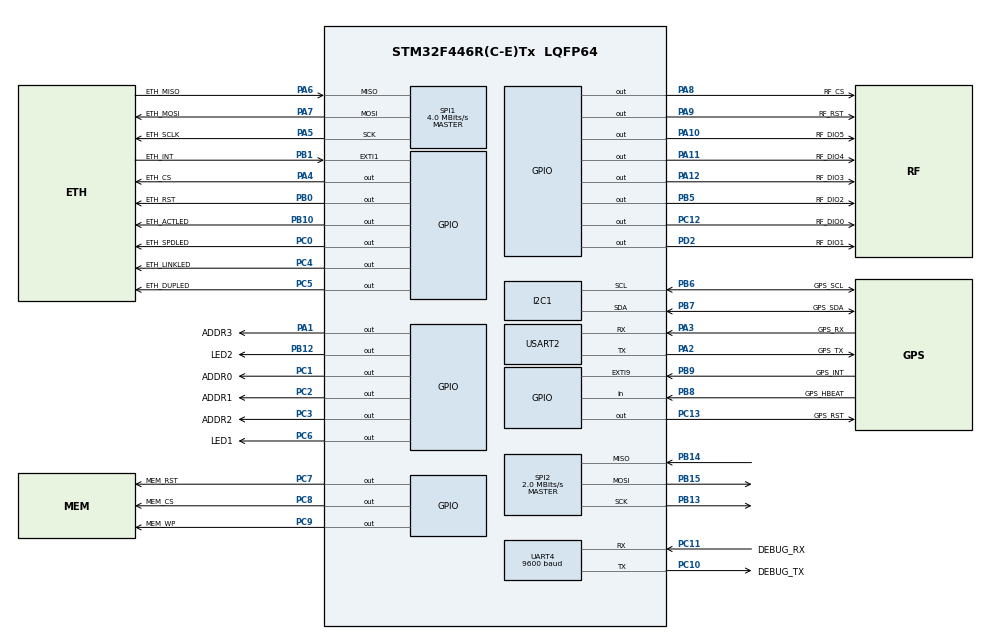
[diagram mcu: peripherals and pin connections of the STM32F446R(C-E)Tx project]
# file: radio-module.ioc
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Mcu.Family=STM32F4
Mcu.Name=STM32F446R(C-E)Tx
Mcu.Package=LQFP64
NVIC.EXTI1_IRQn=true\:0\:0\:false\:false\:true\:true\:true\:true
NVIC.EXTI9_5_IRQn=true\:0\:0\:false\:false\:true\:true\:true\:true
NVIC.I2C1_ER_IRQn=true\:0\:0\:false\:false\:true\:true\:true\:true
NVIC.I2C1_EV_IRQn=true\:0\:0\:false\:false\:true\:true\:true\:true
NVIC.PriorityGroup=NVIC_PRIORITYGROUP_4
NVIC.SPI1_IRQn=true\:0\:0\:false\:false\:true\:true\:true\:true
NVIC.SPI2_IRQn=true\:0\:0\:false\:false\:true\:true\:true\:true
NVIC.UART4_IRQn=true\:0\:0\:false\:false\:true\:true\:true\:true
NVIC.USART2_IRQn=true\:0\:0\:false\:false\:true\:true\:true\:true
PA1.GPIO_Label=ADDR3
PA1.Signal=GPIO_Output
PA10.GPIO_Label=RF_DIO5
PA10.Signal=GPIO_Output
PA11.GPIO_Label=RF_DIO4
PA11.Signal=GPIO_Output
PA12.GPIO_Label=RF_DIO3
PA12.Signal=GPIO_Output
PA2.GPIO_Label=GPS_TX
PA2.Mode=Asynchronous
PA2.Signal=USART2_TX
PA3.GPIO_Label=GPS_RX
PA3.Mode=Asynchronous
PA3.Signal=USART2_RX
PA4.GPIO_Label=ETH_CS
PA4.Signal=GPIO_Output
PA5.GPIO_Label=ETH_SCLK
PA5.Mode=Full_Duplex_Master
PA5.Signal=SPI1_SCK
PA6.GPIO_Label=ETH_MISO
PA6.Mode=Full_Duplex_Master
PA6.Signal=SPI1_MISO
PA7.GPIO_Label=ETH_MOSI
PA7.Mode=Full_Duplex_Master
PA7.Signal=SPI1_MOSI
PA8.GPIO_Label=RF_CS
PA8.Signal=GPIO_Output
PA9.GPIO_Label=RF_RST
PA9.PinState=GPIO_PIN_SET
PA9.Signal=GPIO_Output
PB0.GPIO_Label=ETH_RST
PB0.PinState=GPIO_PIN_SET
PB0.Signal=GPIO_Output
PB1.GPIO_Label=ETH_INT
PB1.Signal=GPXTI1
PB10.GPIO_Label=ETH_ACTLED
PB10.Signal=GPIO_Output
PB12.GPIO_Label=LED2
PB12.Signal=GPIO_Output
PB13.Mode=Full_Duplex_Master
PB13.Signal=SPI2_SCK
PB14.Mode=Full_Duplex_Master
PB14.Signal=SPI2_MISO
PB15.Mode=Full_Duplex_Master
PB15.Signal=SPI2_MOSI
PB5.GPIO_Label=RF_DIO2
PB5.Signal=GPIO_Output
PB6.GPIO_Label=GPS_SCL
PB6.Mode=I2C
PB6.Signal=I2C1_SCL
PB7.GPIO_Label=GPS_SDA
PB7.Mode=I2C
PB7.Signal=I2C1_SDA
PB8.GPIO_Label=GPS_HBEAT
PB8.Signal=GPIO_Input
PB9.GPIO_Label=GPS_INT
PB9.Signal=GPXTI9
PC0.GPIO_Label=ETH_SPDLED
PC0.Signal=GPIO_Output
PC1.GPIO_Label=ADDR0
PC1.Signal=GPIO_Output
PC10.GPIO_Label=DEBUG_TX
PC10.Mode=Asynchronous
PC10.Signal=UART4_TX
PC11.GPIO_Label=DEBUG_RX
PC11.Mode=Asynchronous
PC11.Signal=UART4_RX
PC12.GPIO_Label=RF_DIO0
PC12.Signal=GPIO_Output
PC13.GPIO_Label=GPS_RST
PC13.PinState=GPIO_PIN_SET
PC13.Signal=GPIO_Output
PC2.GPIO_Label=ADDR1
PC2.Signal=GPIO_Output
PC3.GPIO_Label=ADDR2
PC3.Signal=GPIO_Output
PC4.GPIO_Label=ETH_LINKLED
PC4.Signal=GPIO_Output
PC5.GPIO_Label=ETH_DUPLED
PC5.Signal=GPIO_Output
PC6.GPIO_Label=LED1
PC6.Signal=GPIO_Output
PC7.GPIO_Label=MEM_RST
PC7.PinState=GPIO_PIN_SET
PC7.Signal=GPIO_Output
PC8.GPIO_Label=MEM_CS
PC8.Signal=GPIO_Output
PC9.GPIO_Label=MEM_WP
PC9.Signal=GPIO_Output
PD2.GPIO_Label=RF_DIO1
PD2.Signal=GPIO_Output
ProjectManager.HeapSize=0x200
ProjectManager.StackSize=0x400
ProjectManager.TargetToolchain=Makefile
RCC.AHBFreq_Value=16000000
RCC.APB1CLKDivider=RCC_HCLK_DIV4
RCC.APB1Freq_Value=4000000
RCC.APB1TimFreq_Value=8000000
RCC.APB2CLKDivider=RCC_HCLK_DIV2
RCC.APB2Freq_Value=8000000
RCC.APB2TimFreq_Value=16000000
RCC.CortexFreq_Value=16000000
RCC.HCLKFreq_Value=16000000
RCC.PLLM=8
RCC.PLLN=180
RCC.SYSCLKFreq_VALUE=16000000
RCC.USBFreq_Value=180000000
RCC.VCOOutputFreq_Value=360000000
SPI1.CalculateBaudRate=4.0 MBits/s
SPI1.Direction=SPI_DIRECTION_2LINES
SPI1.Mode=SPI_MODE_MASTER
SPI1.VirtualType=VM_MASTER
SPI2.CalculateBaudRate=2.0 MBits/s
SPI2.Direction=SPI_DIRECTION_2LINES
SPI2.Mode=SPI_MODE_MASTER
SPI2.VirtualType=VM_MASTER
UART4.BaudRate=9600
UART4.VirtualMode=Asynchronous
USART2.VirtualMode=VM_ASYNC
board=custom

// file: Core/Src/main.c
/* USER CODE BEGIN Header */
/**
  ******************************************************************************
  * @file           : main.c
  * @brief          : Main program body
  ******************************************************************************
  * @attention
  *
  * Copyright (c) 2022 STMicroelectronics.
  * All rights reserved.
  *
  * This software is licensed under terms that can be found in the LICENSE file
  * in the root directory of this software component.
  * If no LICENSE file comes with this software, it is provided AS-IS.
  *
  ******************************************************************************
  */
/* USER CODE END Header */
#include "main.h"

/* USER CODE BEGIN Includes */

#include <stdio.h>
#include <string.h>

#include "device/platforms/stm32/HAL_GPIODevice.h"
#include "device/platforms/stm32/HAL_UARTDevice.h"
#include "device/platforms/stm32/HAL_SPIDevice.h"
#include "device/peripherals/RFM95W/RFM95W.h"

#include "net/packet/Packet.h"
#include "net/stack/IPv4UDP/IPv4UDPStack.h"
#include "net/stack/IPv4UDP/IPv4UDPSocket.h"

#include "device/platforms/stm32/HAL_GPIODevice.h"
#include "device/platforms/stm32/HAL_UARTDevice.h"
#include "device/platforms/stm32/HAL_SPIDevice.h"

#include "device/peripherals/W5500/W5500.h"

#include "sched/macros.h"
/* USER CODE END Includes */

I2C_HandleTypeDef hi2c1;

SPI_HandleTypeDef hspi1;
SPI_HandleTypeDef hspi2;

UART_HandleTypeDef huart4;
UART_HandleTypeDef huart2;

/* USER CODE BEGIN PV */
static HALSPIDevice *wizSPI = nullptr;
static HALGPIODevice *wizCS = nullptr;
static HALUARTDevice *uartDev = nullptr;

static RFM95W *rfm95w_tx = nullptr;
static RFM95W *rfm95w_rx = nullptr;
static HALUARTDevice *uartDev = nullptr;

static HALSPIDevice *spi2 = nullptr;

static W5500 *w5500 = nullptr;
static IPv4UDPStack *stack = nullptr;
static IPv4UDPSocket *sock = nullptr;
/* USER CODE END PV */

void SystemClock_Config(void);

static void MX_GPIO_Init(void);

static void MX_I2C1_Init(void);

static void MX_SPI1_Init(void);

static void MX_UART4_Init(void);

static void MX_USART2_UART_Init(void);

static void MX_SPI2_Init(void);

/* USER CODE BEGIN 0 */

RetType spiDevPollTask(void *) {
    RESUME();
    CALL(wizSPI->poll());
//    CALL(flashSPI->poll());
    RESET();
    return RET_SUCCESS;
}

RetType netStackInitTask(void *) {
    RESUME();

	RESET();
	return RET_SUCCESS;

}

RetType rfmTxTask(){
	RESUME();

	RESET();
	return RET_SUCCESS;
}

RetType rfmRxTask(){
	RESUME();

	RESET();
	return RET_SUCCESS;
}

RetType radioInitTask(){
	RESUME();

	RESET();
	return RET_SUCCESS;
}
/* USER CODE END 0 */

    static W5500 wiznet(*wizSPI, *wizCS);
    w5500 = &wiznet;

    static IPv4UDPStack iPv4UdpStack{10, 10, 10, 1, \
                              255, 255, 255, 0,
                                     *w5500};
    stack = &iPv4UdpStack;

    static uint8_t ip_addr[4] = {192, 168, 1, 10};
    static uint8_t subnet_mask[4] = {255, 255, 255, 0};
    static uint8_t gateway_addr[4] = {192, 168, 1, 1};
    static uint8_t mac_addr[6] = {0x00, 0x00, 0x00, 0x00, 0x00, 0x00};
    static IPv4UDPSocket::addr_t addr;

    sock = stack->get_socket();
    addr.ip[0] = addr.ip[1] = addr.ip[2] = addr.ip[3] = 0;
    addr.port = 8000;
    sock->bind(addr); // TODO: Error handling

    ipv4::IPv4Addr_t temp_addr;
    ipv4::IPv4Address(10, 10, 10, 69, &temp_addr);
    stack->add_multicast(temp_addr);

    CALL(uartDev->write((uint8_t *) "W5500: Initializing\r\n", 23));
    RetType ret = CALL(wiznet.init(gateway_addr, subnet_mask, mac_addr, ip_addr));
    if (ret != RET_SUCCESS) {
        CALL(uartDev->write((uint8_t *) "W5500: Failed to initialize\r\n", 29));
        goto netStackInitDone;
    }

    CALL(uartDev->write((uint8_t *) "W5500: Initialized\r\n", 20));

    if (RET_SUCCESS != stack->init()) {
        CALL(uartDev->write((uint8_t *) "Failed to initialize network stack\r\n", 35));
        goto netStackInitDone;
    }

    sched_start(netStackInitTask, {});

    netStackInitDone:
    RESET();
    return RET_ERROR; // Kill task
}

/* USER CODE END 0 */

int main(void) {

    /* MCU Configuration--------------------------------------------------------*/

    /* Reset of all peripherals, Initializes the Flash interface and the Systick. */
    HAL_Init();

    /* Configure the system clock */
    SystemClock_Config();

    /* Initialize all configured peripherals */
    MX_GPIO_Init();
    MX_I2C1_Init();
    MX_SPI1_Init();
    MX_UART4_Init();
    MX_USART2_UART_Init();
    MX_SPI2_Init();
    /* USER CODE BEGIN 2 */
    HAL_GPIO_WritePin(GPS_RST_GPIO_Port, GPS_RST_Pin, GPIO_PIN_SET);
    HAL_GPIO_WritePin(GPS_INT_GPIO_Port, GPS_INT_Pin, GPIO_PIN_RESET);

    if (!sched_init(&HAL_GetTick)) {
        HAL_UART_Transmit_IT(&huart2, (uint8_t *) "Failed to init scheduler\n\r", 30);
        return -1;
    }

    HALUARTDevice uart("UART", &huart4);
    RetType ret = uart.init();
    if (ret != RET_SUCCESS) {
        HAL_UART_Transmit_IT(&huart2, (uint8_t *) "Failed to init UART Device. Exiting.\n\r", 38);
        return -1;
    }
    uartDev = &uart;

    static HALSPIDevice wizSpi("WIZNET SPI", &hspi1);
    ret = wizSpi.init();
    wizSPI = &wizSpi;

    HALGPIODevice wizChipSelect("Wiznet CS", ETH_CS_GPIO_Port, ETH_CS_Pin);
    ret = wizChipSelect.init();
    wizCS = &wizChipSelect;

    sched_start(spiDevPollTask, {});
    sched_start(netStackInitTask, {});

    /* USER CODE END 2 */

    /* Infinite loop */
    while (1) {
        sched_dispatch();
        HAL_UART_Transmit(&huart4, (uint8_t *) "Hello World\n\r", 13, 1000);
        HAL_Delay(500);
    }
}

void SystemClock_Config(void) {
    RCC_OscInitTypeDef RCC_OscInitStruct = {0};
    RCC_ClkInitTypeDef RCC_ClkInitStruct = {0};

    /** Configure the main internal regulator output voltage
    */
    __HAL_RCC_PWR_CLK_ENABLE();
    __HAL_PWR_VOLTAGESCALING_CONFIG(PWR_REGULATOR_VOLTAGE_SCALE3);

    /** Initializes the RCC Oscillators according to the specified parameters
    * in the RCC_OscInitTypeDef structure.
    */
    RCC_OscInitStruct.OscillatorType = RCC_OSCILLATORTYPE_HSI;
    RCC_OscInitStruct.HSIState = RCC_HSI_ON;
    RCC_OscInitStruct.HSICalibrationValue = RCC_HSICALIBRATION_DEFAULT;
    RCC_OscInitStruct.PLL.PLLState = RCC_PLL_NONE;
    if (HAL_RCC_OscConfig(&RCC_OscInitStruct) != HAL_OK) {
        Error_Handler();
    }

    /** Initializes the CPU, AHB and APB buses clocks
    */
    RCC_ClkInitStruct.ClockType = RCC_CLOCKTYPE_HCLK | RCC_CLOCKTYPE_SYSCLK
                                  | RCC_CLOCKTYPE_PCLK1 | RCC_CLOCKTYPE_PCLK2;
    RCC_ClkInitStruct.SYSCLKSource = RCC_SYSCLKSOURCE_HSI;
    RCC_ClkInitStruct.AHBCLKDivider = RCC_SYSCLK_DIV1;
    RCC_ClkInitStruct.APB1CLKDivider = RCC_HCLK_DIV1;
    RCC_ClkInitStruct.APB2CLKDivider = RCC_HCLK_DIV1;

    if (HAL_RCC_ClockConfig(&RCC_ClkInitStruct, FLASH_LATENCY_0) != HAL_OK) {
        Error_Handler();
    }
}

static void MX_I2C1_Init(void) {

    hi2c1.Instance = I2C1;
    hi2c1.Init.ClockSpeed = 100000;
    hi2c1.Init.DutyCycle = I2C_DUTYCYCLE_2;
    hi2c1.Init.OwnAddress1 = 0;
    hi2c1.Init.AddressingMode = I2C_ADDRESSINGMODE_7BIT;
    hi2c1.Init.DualAddressMode = I2C_DUALADDRESS_DISABLE;
    hi2c1.Init.OwnAddress2 = 0;
    hi2c1.Init.GeneralCallMode = I2C_GENERALCALL_DISABLE;
    hi2c1.Init.NoStretchMode = I2C_NOSTRETCH_DISABLE;
    if (HAL_I2C_Init(&hi2c1) != HAL_OK) {
        Error_Handler();
    }

}

static void MX_SPI1_Init(void) {

    /* SPI1 parameter configuration*/
    hspi1.Instance = SPI1;
    hspi1.Init.Mode = SPI_MODE_MASTER;
    hspi1.Init.Direction = SPI_DIRECTION_2LINES;
    hspi1.Init.DataSize = SPI_DATASIZE_8BIT;
    hspi1.Init.CLKPolarity = SPI_POLARITY_LOW;
    hspi1.Init.CLKPhase = SPI_PHASE_1EDGE;
    hspi1.Init.NSS = SPI_NSS_SOFT;
    hspi1.Init.BaudRatePrescaler = SPI_BAUDRATEPRESCALER_2;
    hspi1.Init.FirstBit = SPI_FIRSTBIT_MSB;
    hspi1.Init.TIMode = SPI_TIMODE_DISABLE;
    hspi1.Init.CRCCalculation = SPI_CRCCALCULATION_DISABLE;
    hspi1.Init.CRCPolynomial = 10;
    if (HAL_SPI_Init(&hspi1) != HAL_OK) {
        Error_Handler();
    }

}

static void MX_SPI2_Init(void) {

    /* SPI2 parameter configuration*/
    hspi2.Instance = SPI2;
    hspi2.Init.Mode = SPI_MODE_MASTER;
    hspi2.Init.Direction = SPI_DIRECTION_2LINES;
    hspi2.Init.DataSize = SPI_DATASIZE_8BIT;
    hspi2.Init.CLKPolarity = SPI_POLARITY_LOW;
    hspi2.Init.CLKPhase = SPI_PHASE_1EDGE;
    hspi2.Init.NSS = SPI_NSS_SOFT;
    hspi2.Init.BaudRatePrescaler = SPI_BAUDRATEPRESCALER_2;
    hspi2.Init.FirstBit = SPI_FIRSTBIT_MSB;
    hspi2.Init.TIMode = SPI_TIMODE_DISABLE;
    hspi2.Init.CRCCalculation = SPI_CRCCALCULATION_DISABLE;
    hspi2.Init.CRCPolynomial = 10;
    if (HAL_SPI_Init(&hspi2) != HAL_OK) {
        Error_Handler();
    }

}

static void MX_UART4_Init(void) {

    huart4.Instance = UART4;
    huart4.Init.BaudRate = 9600;
    huart4.Init.WordLength = UART_WORDLENGTH_8B;
    huart4.Init.StopBits = UART_STOPBITS_1;
    huart4.Init.Parity = UART_PARITY_NONE;
    huart4.Init.Mode = UART_MODE_TX_RX;
    huart4.Init.HwFlowCtl = UART_HWCONTROL_NONE;
    huart4.Init.OverSampling = UART_OVERSAMPLING_16;
    if (HAL_UART_Init(&huart4) != HAL_OK) {
        Error_Handler();
    }

}

static void MX_USART2_UART_Init(void) {

    huart2.Instance = USART2;
    huart2.Init.BaudRate = 115200;
    huart2.Init.WordLength = UART_WORDLENGTH_8B;
    huart2.Init.StopBits = UART_STOPBITS_1;
    huart2.Init.Parity = UART_PARITY_NONE;
    huart2.Init.Mode = UART_MODE_TX_RX;
    huart2.Init.HwFlowCtl = UART_HWCONTROL_NONE;
    huart2.Init.OverSampling = UART_OVERSAMPLING_16;
    if (HAL_UART_Init(&huart2) != HAL_OK) {
        Error_Handler();
    }

}

static void MX_GPIO_Init(void) {
    GPIO_InitTypeDef GPIO_InitStruct = {0};

    /* GPIO Ports Clock Enable */
    __HAL_RCC_GPIOC_CLK_ENABLE();
    __HAL_RCC_GPIOA_CLK_ENABLE();
    __HAL_RCC_GPIOB_CLK_ENABLE();
    __HAL_RCC_GPIOD_CLK_ENABLE();

    /*Configure GPIO pin Output Level */
    HAL_GPIO_WritePin(GPIOC, GPS_RST_Pin | ETH_SPDLED_Pin | ADDR0_Pin | ADDR1_Pin
                             | ADDR2_Pin | ETH_LINKLED_Pin | ETH_DUPLED_Pin | LED1_Pin
                             | MEM_RST_Pin | MEM_CS_Pin | MEM_WP_Pin | RF_DIO0_Pin, GPIO_PIN_RESET);

    /*Configure GPIO pin Output Level */
    HAL_GPIO_WritePin(GPIOA, ADDR3_Pin | ETH_CS_Pin | RF_CS_Pin | RF_RST_Pin
                             | RF_DIO5_Pin | RF_DIO4_Pin | RF_DIO3_Pin, GPIO_PIN_RESET);

    /*Configure GPIO pin Output Level */
    HAL_GPIO_WritePin(GPIOB, ETH_RST_Pin | ETH_ACTLED_Pin | LED2_Pin | RF_DIO2_Pin, GPIO_PIN_RESET);

    /*Configure GPIO pin Output Level */
    HAL_GPIO_WritePin(RF_DIO1_GPIO_Port, RF_DIO1_Pin, GPIO_PIN_RESET);

    /*Configure GPIO pins : GPS_RST_Pin ETH_SPDLED_Pin ADDR0_Pin ADDR1_Pin
                             ADDR2_Pin ETH_LINKLED_Pin ETH_DUPLED_Pin LED1_Pin
                             MEM_RST_Pin MEM_CS_Pin MEM_WP_Pin RF_DIO0_Pin */
    GPIO_InitStruct.Pin = GPS_RST_Pin | ETH_SPDLED_Pin | ADDR0_Pin | ADDR1_Pin
                          | ADDR2_Pin | ETH_LINKLED_Pin | ETH_DUPLED_Pin | LED1_Pin
                          | MEM_RST_Pin | MEM_CS_Pin | MEM_WP_Pin | RF_DIO0_Pin;
    GPIO_InitStruct.Mode = GPIO_MODE_OUTPUT_PP;
    GPIO_InitStruct.Pull = GPIO_NOPULL;
    GPIO_InitStruct.Speed = GPIO_SPEED_FREQ_LOW;
    HAL_GPIO_Init(GPIOC, &GPIO_InitStruct);

    /*Configure GPIO pins : ADDR3_Pin ETH_CS_Pin RF_CS_Pin RF_RST_Pin
                             RF_DIO5_Pin RF_DIO4_Pin RF_DIO3_Pin */
    GPIO_InitStruct.Pin = ADDR3_Pin | ETH_CS_Pin | RF_CS_Pin | RF_RST_Pin
                          | RF_DIO5_Pin | RF_DIO4_Pin | RF_DIO3_Pin;
    GPIO_InitStruct.Mode = GPIO_MODE_OUTPUT_PP;
    GPIO_InitStruct.Pull = GPIO_NOPULL;
    GPIO_InitStruct.Speed = GPIO_SPEED_FREQ_LOW;
    HAL_GPIO_Init(GPIOA, &GPIO_InitStruct);

    /*Configure GPIO pins : ETH_RST_Pin ETH_ACTLED_Pin LED2_Pin RF_DIO2_Pin */
    GPIO_InitStruct.Pin = ETH_RST_Pin | ETH_ACTLED_Pin | LED2_Pin | RF_DIO2_Pin;
    GPIO_InitStruct.Mode = GPIO_MODE_OUTPUT_PP;
    GPIO_InitStruct.Pull = GPIO_NOPULL;
    GPIO_InitStruct.Speed = GPIO_SPEED_FREQ_LOW;
    HAL_GPIO_Init(GPIOB, &GPIO_InitStruct);

    /*Configure GPIO pins : ETH_INT_Pin GPS_HBEAT_Pin GPS_INT_Pin */
    GPIO_InitStruct.Pin = ETH_INT_Pin | GPS_HBEAT_Pin | GPS_INT_Pin;
    GPIO_InitStruct.Mode = GPIO_MODE_INPUT;
    GPIO_InitStruct.Pull = GPIO_NOPULL;
    HAL_GPIO_Init(GPIOB, &GPIO_InitStruct);

    /*Configure GPIO pin : RF_DIO1_Pin */
    GPIO_InitStruct.Pin = RF_DIO1_Pin;
    GPIO_InitStruct.Mode = GPIO_MODE_OUTPUT_PP;
    GPIO_InitStruct.Pull = GPIO_NOPULL;
    GPIO_InitStruct.Speed = GPIO_SPEED_FREQ_LOW;
    HAL_GPIO_Init(RF_DIO1_GPIO_Port, &GPIO_InitStruct);

}

void Error_Handler(void) {
    __disable_irq();
    while (1) {
    }
}
